VERSION 5.7 ;
  NOWIREEXTENSIONATPIN ON ;
  DIVIDERCHAR "/" ;
  BUSBITCHARS "[]" ;
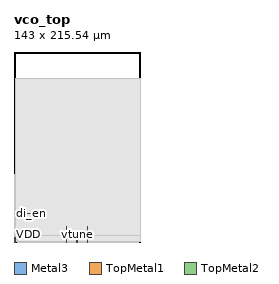
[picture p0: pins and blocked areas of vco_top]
MACRO vco_top
  CLASS BLOCK ;
  FOREIGN vco_top ;
  ORIGIN 0.000 0.000 ;
  SIZE 143.000 BY 215.540 ;
  PIN di_en
    ANTENNAGATEAREA 0.195000 ;
    PORT
      LAYER Metal3 ;
        RECT 0.000 32.590 30.350 32.890 ;
    END
  END di_en
  PIN vtune
    ANTENNADIFFAREA 52.605900 ;
    PORT
      LAYER Metal3 ;
        RECT 71.200 0.000 71.800 2.695 ;
    END
  END vtune
  PIN rf_out_p
    ANTENNADIFFAREA 4.560000 ;
    PORT
      LAYER Metal3 ;
        RECT 83.200 0.000 83.800 17.020 ;
    END
  END rf_out_p
  PIN rf_out_n
    ANTENNADIFFAREA 4.560000 ;
    PORT
      LAYER Metal3 ;
        RECT 59.200 0.000 59.800 17.020 ;
    END
  END rf_out_n
  PIN VDD
    USE POWER ;
    PORT
      LAYER TopMetal1 ;
        RECT 0.000 0.000 2.000 1.640 ;
    END
  END VDD
  PIN VSS
    USE GROUND ;
    PORT
      LAYER TopMetal2 ;
        RECT 0.000 0.500 2.000 5.300 ;
    END
  END VSS
  OBS
      LAYER GatPoly ;
        RECT 5.370 0.330 141.980 77.000 ;
      LAYER Metal1 ;
        RECT 0.500 0.390 141.785 76.970 ;
      LAYER Metal2 ;
        RECT 0.735 0.440 141.780 74.800 ;
      LAYER Metal3 ;
        RECT 0.735 33.100 141.780 74.825 ;
        RECT 30.560 32.380 141.780 33.100 ;
        RECT 0.735 17.230 141.780 32.380 ;
        RECT 0.735 0.390 58.990 17.230 ;
        RECT 60.010 2.905 82.990 17.230 ;
        RECT 60.010 0.390 70.990 2.905 ;
        RECT 72.010 0.390 82.990 2.905 ;
        RECT 84.010 0.390 141.780 17.230 ;
      LAYER Metal4 ;
        RECT 0.600 0.120 141.780 75.000 ;
      LAYER Metal5 ;
        RECT 0.000 0.510 143.000 76.100 ;
      LAYER TopMetal1 ;
        RECT 1.570 3.280 141.290 185.520 ;
        RECT 3.640 0.000 141.290 3.280 ;
      LAYER TopMetal2 ;
        RECT 2.000 7.300 143.000 185.520 ;
        RECT 4.000 0.500 143.000 7.300 ;
  END
END vco_top
END LIBRARY

